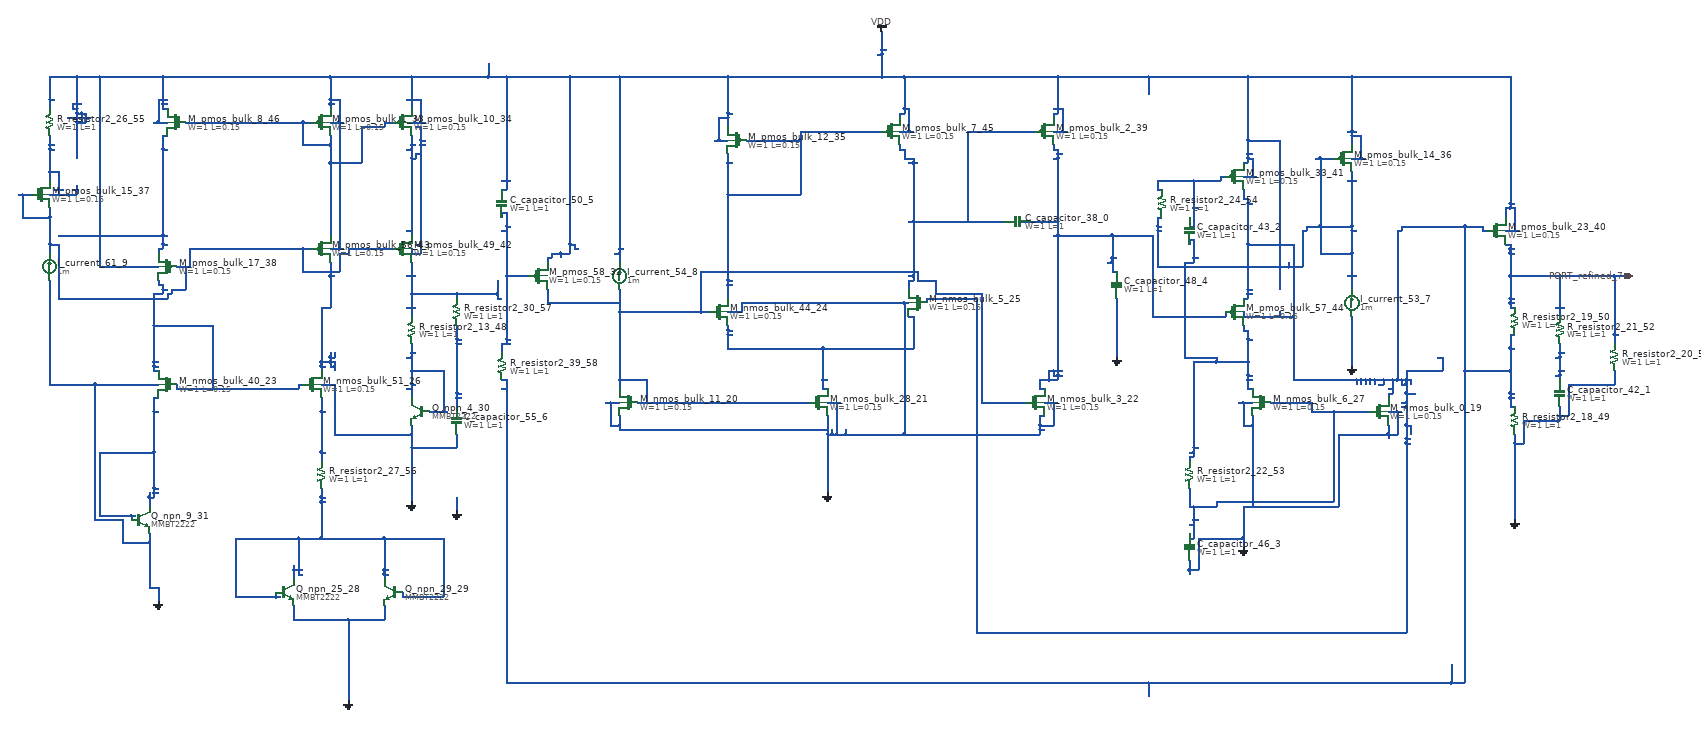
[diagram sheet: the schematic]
v {xschem version=3.4.8 file_version=1.2}
G {}
K {}
V {}
S {}
E {}
C {sky130_fd_pr/cap_mim_m3_1.sym} 2260 500 1 0 {name="C_capacitor_38_0" model=cap_mim_m3_1 W=1 L=1 MF=1 spiceprefix=X}
C {sky130_fd_pr/cap_mim_m3_1.sym} 3460 880 2 0 {name="C_capacitor_42_1" model=cap_mim_m3_1 W=1 L=1 MF=1 spiceprefix=X}
C {sky130_fd_pr/cap_mim_m3_1.sym} 2640 520 2 0 {name="C_capacitor_43_2" model=cap_mim_m3_1 W=1 L=1 MF=1 spiceprefix=X}
C {sky130_fd_pr/cap_mim_m3_1.sym} 2640 1220 2 0 {name="C_capacitor_46_3" model=cap_mim_m3_1 W=1 L=1 MF=1 spiceprefix=X}
C {sky130_fd_pr/cap_mim_m3_1.sym} 2480 640 2 0 {name="C_capacitor_48_4" model=cap_mim_m3_1 W=1 L=1 MF=1 spiceprefix=X}
C {sky130_fd_pr/cap_mim_m3_1.sym} 1120 460 2 0 {name="C_capacitor_50_5" model=cap_mim_m3_1 W=1 L=1 MF=1 spiceprefix=X}
C {sky130_fd_pr/cap_mim_m3_1.sym} 1020 940 2 0 {name="C_capacitor_55_6" model=cap_mim_m3_1 W=1 L=1 MF=1 spiceprefix=X}
C {devices/isource.sym} 3000 680 2 0 {name="I_current_53_7" value=1m}
C {devices/isource.sym} 1380 620 2 0 {name="I_current_54_8" value=1m}
C {devices/isource.sym} 120 600 2 0 {name="I_current_61_9" value=1m}
C {devices/gnd.sym} 780 1560 0 0 {name="l_gnd_31_10" lab="GND"}
C {devices/gnd.sym} 360 1340 0 0 {name="l_gnd_32_11" lab="GND"}
C {devices/gnd.sym} 3000 820 0 0 {name="l_gnd_34_12" lab="GND"}
C {devices/gnd.sym} 3360 1160 0 0 {name="l_gnd_35_13" lab="GND"}
C {devices/gnd.sym} 920 1120 0 0 {name="l_gnd_36_14" lab="GND"}
C {devices/gnd.sym} 2480 800 0 0 {name="l_gnd_37_15" lab="GND"}
C {devices/gnd.sym} 1020 1140 0 0 {name="l_gnd_41_16" lab="GND"}
C {devices/gnd.sym} 1840 1100 0 0 {name="l_gnd_45_17" lab="GND"}
C {devices/gnd.sym} 2760 1220 0 0 {name="l_gnd_52_18" lab="GND"}
C {sky130_fd_pr/nfet_01v8.sym} 3060 920 0 0 {name="M_nmos_bulk_0_19"
W=1
L=0.15
nf=1 
mult=1
ad="expr('int((@nf + 1)/2) * @W / @nf * 0.29')"
pd="expr('2*int((@nf + 1)/2) * (@W / @nf + 0.29)')"
as="expr('int((@nf + 2)/2) * @W / @nf * 0.29')"
ps="expr('2*int((@nf + 2)/2) * (@W / @nf + 0.29)')"
nrd="expr('0.29 / @W ')" nrs="expr('0.29 / @W ')"
sa=0 sb=0 sd=0
model=nfet_01v8
spiceprefix=X
}
C {sky130_fd_pr/nfet_01v8.sym} 1400 900 0 1 {name="M_nmos_bulk_11_20"
W=1
L=0.15
nf=1 
mult=1
ad="expr('int((@nf + 1)/2) * @W / @nf * 0.29')"
pd="expr('2*int((@nf + 1)/2) * (@W / @nf + 0.29)')"
as="expr('int((@nf + 2)/2) * @W / @nf * 0.29')"
ps="expr('2*int((@nf + 2)/2) * (@W / @nf + 0.29)')"
nrd="expr('0.29 / @W ')" nrs="expr('0.29 / @W ')"
sa=0 sb=0 sd=0
model=nfet_01v8
spiceprefix=X
}
C {sky130_fd_pr/nfet_01v8.sym} 1820 900 0 0 {name="M_nmos_bulk_28_21"
W=1
L=0.15
nf=1 
mult=1
ad="expr('int((@nf + 1)/2) * @W / @nf * 0.29')"
pd="expr('2*int((@nf + 1)/2) * (@W / @nf + 0.29)')"
as="expr('int((@nf + 2)/2) * @W / @nf * 0.29')"
ps="expr('2*int((@nf + 2)/2) * (@W / @nf + 0.29)')"
nrd="expr('0.29 / @W ')" nrs="expr('0.29 / @W ')"
sa=0 sb=0 sd=0
model=nfet_01v8
spiceprefix=X
}
C {sky130_fd_pr/nfet_01v8.sym} 2300 900 0 0 {name="M_nmos_bulk_3_22"
W=1
L=0.15
nf=1 
mult=1
ad="expr('int((@nf + 1)/2) * @W / @nf * 0.29')"
pd="expr('2*int((@nf + 1)/2) * (@W / @nf + 0.29)')"
as="expr('int((@nf + 2)/2) * @W / @nf * 0.29')"
ps="expr('2*int((@nf + 2)/2) * (@W / @nf + 0.29)')"
nrd="expr('0.29 / @W ')" nrs="expr('0.29 / @W ')"
sa=0 sb=0 sd=0
model=nfet_01v8
spiceprefix=X
}
C {sky130_fd_pr/nfet_01v8.sym} 380 860 0 1 {name="M_nmos_bulk_40_23"
W=1
L=0.15
nf=1 
mult=1
ad="expr('int((@nf + 1)/2) * @W / @nf * 0.29')"
pd="expr('2*int((@nf + 1)/2) * (@W / @nf + 0.29)')"
as="expr('int((@nf + 2)/2) * @W / @nf * 0.29')"
ps="expr('2*int((@nf + 2)/2) * (@W / @nf + 0.29)')"
nrd="expr('0.29 / @W ')" nrs="expr('0.29 / @W ')"
sa=0 sb=0 sd=0
model=nfet_01v8
spiceprefix=X
}
C {sky130_fd_pr/nfet_01v8.sym} 1600 700 0 0 {name="M_nmos_bulk_44_24"
W=1
L=0.15
nf=1 
mult=1
ad="expr('int((@nf + 1)/2) * @W / @nf * 0.29')"
pd="expr('2*int((@nf + 1)/2) * (@W / @nf + 0.29)')"
as="expr('int((@nf + 2)/2) * @W / @nf * 0.29')"
ps="expr('2*int((@nf + 2)/2) * (@W / @nf + 0.29)')"
nrd="expr('0.29 / @W ')" nrs="expr('0.29 / @W ')"
sa=0 sb=0 sd=0
model=nfet_01v8
spiceprefix=X
}
C {sky130_fd_pr/nfet_01v8.sym} 2040 680 0 1 {name="M_nmos_bulk_5_25"
W=1
L=0.15
nf=1 
mult=1
ad="expr('int((@nf + 1)/2) * @W / @nf * 0.29')"
pd="expr('2*int((@nf + 1)/2) * (@W / @nf + 0.29)')"
as="expr('int((@nf + 2)/2) * @W / @nf * 0.29')"
ps="expr('2*int((@nf + 2)/2) * (@W / @nf + 0.29)')"
nrd="expr('0.29 / @W ')" nrs="expr('0.29 / @W ')"
sa=0 sb=0 sd=0
model=nfet_01v8
spiceprefix=X
}
C {sky130_fd_pr/nfet_01v8.sym} 700 860 0 0 {name="M_nmos_bulk_51_26"
W=1
L=0.15
nf=1 
mult=1
ad="expr('int((@nf + 1)/2) * @W / @nf * 0.29')"
pd="expr('2*int((@nf + 1)/2) * (@W / @nf + 0.29)')"
as="expr('int((@nf + 2)/2) * @W / @nf * 0.29')"
ps="expr('2*int((@nf + 2)/2) * (@W / @nf + 0.29)')"
nrd="expr('0.29 / @W ')" nrs="expr('0.29 / @W ')"
sa=0 sb=0 sd=0
model=nfet_01v8
spiceprefix=X
}
C {sky130_fd_pr/nfet_01v8.sym} 2800 900 0 1 {name="M_nmos_bulk_6_27"
W=1
L=0.15
nf=1 
mult=1
ad="expr('int((@nf + 1)/2) * @W / @nf * 0.29')"
pd="expr('2*int((@nf + 1)/2) * (@W / @nf + 0.29)')"
as="expr('int((@nf + 2)/2) * @W / @nf * 0.29')"
ps="expr('2*int((@nf + 2)/2) * (@W / @nf + 0.29)')"
nrd="expr('0.29 / @W ')" nrs="expr('0.29 / @W ')"
sa=0 sb=0 sd=0
model=nfet_01v8
spiceprefix=X
}
C {devices/npn.sym} 640 1320 0 0 {name="Q_npn_25_28"
model=MMBT2222
device=MMBT2222
footprint=SOT23
area=1
m=1}
C {devices/npn.sym} 880 1320 0 1 {name="Q_npn_29_29"
model=MMBT2222
device=MMBT2222
footprint=SOT23
area=1
m=1}
C {devices/npn.sym} 940 920 0 1 {name="Q_npn_4_30"
model=MMBT2222
device=MMBT2222
footprint=SOT23
area=1
m=1}
C {devices/npn.sym} 320 1160 0 0 {name="Q_npn_9_31"
model=MMBT2222
device=MMBT2222
footprint=SOT23
area=1
m=1}
C {sky130_fd_pr/pfet3_01v8.sym} 1200 620 0 0 {name="M_pmos_58_32"
W=1
L=0.15
body=VDD
nf=1
mult=1
ad="expr('int((@nf + 1)/2) * @W / @nf * 0.29')"
pd="expr('2*int((@nf + 1)/2) * (@W / @nf + 0.29)')"
as="expr('int((@nf + 2)/2) * @W / @nf * 0.29')"
ps="expr('2*int((@nf + 2)/2) * (@W / @nf + 0.29)')"
nrd="expr('0.29 / @W ')" nrs="expr('0.29 / @W ')"
sa=0 sb=0 sd=0
model=pfet_01v8
spiceprefix=X
}
C {sky130_fd_pr/pfet_01v8.sym} 720 280 0 0 {name="M_pmos_bulk_1_33"
W=1
L=0.15
nf=1
mult=1
ad="expr('int((@nf + 1)/2) * @W / @nf * 0.29')"
pd="expr('2*int((@nf + 1)/2) * (@W / @nf + 0.29)')"
as="expr('int((@nf + 2)/2) * @W / @nf * 0.29')"
ps="expr('2*int((@nf + 2)/2) * (@W / @nf + 0.29)')"
nrd="expr('0.29 / @W ')" nrs="expr('0.29 / @W ')"
sa=0 sb=0 sd=0
model=pfet_01v8
spiceprefix=X
}
C {sky130_fd_pr/pfet_01v8.sym} 900 280 0 0 {name="M_pmos_bulk_10_34"
W=1
L=0.15
nf=1
mult=1
ad="expr('int((@nf + 1)/2) * @W / @nf * 0.29')"
pd="expr('2*int((@nf + 1)/2) * (@W / @nf + 0.29)')"
as="expr('int((@nf + 2)/2) * @W / @nf * 0.29')"
ps="expr('2*int((@nf + 2)/2) * (@W / @nf + 0.29)')"
nrd="expr('0.29 / @W ')" nrs="expr('0.29 / @W ')"
sa=0 sb=0 sd=0
model=pfet_01v8
spiceprefix=X
}
C {sky130_fd_pr/pfet_01v8.sym} 1640 320 0 1 {name="M_pmos_bulk_12_35"
W=1
L=0.15
nf=1
mult=1
ad="expr('int((@nf + 1)/2) * @W / @nf * 0.29')"
pd="expr('2*int((@nf + 1)/2) * (@W / @nf + 0.29)')"
as="expr('int((@nf + 2)/2) * @W / @nf * 0.29')"
ps="expr('2*int((@nf + 2)/2) * (@W / @nf + 0.29)')"
nrd="expr('0.29 / @W ')" nrs="expr('0.29 / @W ')"
sa=0 sb=0 sd=0
model=pfet_01v8
spiceprefix=X
}
C {sky130_fd_pr/pfet_01v8.sym} 2980 360 0 0 {name="M_pmos_bulk_14_36"
W=1
L=0.15
nf=1
mult=1
ad="expr('int((@nf + 1)/2) * @W / @nf * 0.29')"
pd="expr('2*int((@nf + 1)/2) * (@W / @nf + 0.29)')"
as="expr('int((@nf + 2)/2) * @W / @nf * 0.29')"
ps="expr('2*int((@nf + 2)/2) * (@W / @nf + 0.29)')"
nrd="expr('0.29 / @W ')" nrs="expr('0.29 / @W ')"
sa=0 sb=0 sd=0
model=pfet_01v8
spiceprefix=X
}
C {sky130_fd_pr/pfet_01v8.sym} 100 440 0 0 {name="M_pmos_bulk_15_37"
W=1
L=0.15
nf=1
mult=1
ad="expr('int((@nf + 1)/2) * @W / @nf * 0.29')"
pd="expr('2*int((@nf + 1)/2) * (@W / @nf + 0.29)')"
as="expr('int((@nf + 2)/2) * @W / @nf * 0.29')"
ps="expr('2*int((@nf + 2)/2) * (@W / @nf + 0.29)')"
nrd="expr('0.29 / @W ')" nrs="expr('0.29 / @W ')"
sa=0 sb=0 sd=0
model=pfet_01v8
spiceprefix=X
}
C {sky130_fd_pr/pfet_01v8.sym} 380 600 0 1 {name="M_pmos_bulk_17_38"
W=1
L=0.15
nf=1
mult=1
ad="expr('int((@nf + 1)/2) * @W / @nf * 0.29')"
pd="expr('2*int((@nf + 1)/2) * (@W / @nf + 0.29)')"
as="expr('int((@nf + 2)/2) * @W / @nf * 0.29')"
ps="expr('2*int((@nf + 2)/2) * (@W / @nf + 0.29)')"
nrd="expr('0.29 / @W ')" nrs="expr('0.29 / @W ')"
sa=0 sb=0 sd=0
model=pfet_01v8
spiceprefix=X
}
C {sky130_fd_pr/pfet_01v8.sym} 2320 300 0 0 {name="M_pmos_bulk_2_39"
W=1
L=0.15
nf=1
mult=1
ad="expr('int((@nf + 1)/2) * @W / @nf * 0.29')"
pd="expr('2*int((@nf + 1)/2) * (@W / @nf + 0.29)')"
as="expr('int((@nf + 2)/2) * @W / @nf * 0.29')"
ps="expr('2*int((@nf + 2)/2) * (@W / @nf + 0.29)')"
nrd="expr('0.29 / @W ')" nrs="expr('0.29 / @W ')"
sa=0 sb=0 sd=0
model=pfet_01v8
spiceprefix=X
}
C {sky130_fd_pr/pfet_01v8.sym} 3320 520 0 0 {name="M_pmos_bulk_23_40"
W=1
L=0.15
nf=1
mult=1
ad="expr('int((@nf + 1)/2) * @W / @nf * 0.29')"
pd="expr('2*int((@nf + 1)/2) * (@W / @nf + 0.29)')"
as="expr('int((@nf + 2)/2) * @W / @nf * 0.29')"
ps="expr('2*int((@nf + 2)/2) * (@W / @nf + 0.29)')"
nrd="expr('0.29 / @W ')" nrs="expr('0.29 / @W ')"
sa=0 sb=0 sd=0
model=pfet_01v8
spiceprefix=X
}
C {sky130_fd_pr/pfet_01v8.sym} 2740 400 0 0 {name="M_pmos_bulk_33_41"
W=1
L=0.15
nf=1
mult=1
ad="expr('int((@nf + 1)/2) * @W / @nf * 0.29')"
pd="expr('2*int((@nf + 1)/2) * (@W / @nf + 0.29)')"
as="expr('int((@nf + 2)/2) * @W / @nf * 0.29')"
ps="expr('2*int((@nf + 2)/2) * (@W / @nf + 0.29)')"
nrd="expr('0.29 / @W ')" nrs="expr('0.29 / @W ')"
sa=0 sb=0 sd=0
model=pfet_01v8
spiceprefix=X
}
C {sky130_fd_pr/pfet_01v8.sym} 900 560 0 0 {name="M_pmos_bulk_49_42"
W=1
L=0.15
nf=1
mult=1
ad="expr('int((@nf + 1)/2) * @W / @nf * 0.29')"
pd="expr('2*int((@nf + 1)/2) * (@W / @nf + 0.29)')"
as="expr('int((@nf + 2)/2) * @W / @nf * 0.29')"
ps="expr('2*int((@nf + 2)/2) * (@W / @nf + 0.29)')"
nrd="expr('0.29 / @W ')" nrs="expr('0.29 / @W ')"
sa=0 sb=0 sd=0
model=pfet_01v8
spiceprefix=X
}
C {sky130_fd_pr/pfet_01v8.sym} 720 560 2 1 {name="M_pmos_bulk_56_43"
W=1
L=0.15
nf=1
mult=1
ad="expr('int((@nf + 1)/2) * @W / @nf * 0.29')"
pd="expr('2*int((@nf + 1)/2) * (@W / @nf + 0.29)')"
as="expr('int((@nf + 2)/2) * @W / @nf * 0.29')"
ps="expr('2*int((@nf + 2)/2) * (@W / @nf + 0.29)')"
nrd="expr('0.29 / @W ')" nrs="expr('0.29 / @W ')"
sa=0 sb=0 sd=0
model=pfet_01v8
spiceprefix=X
}
C {sky130_fd_pr/pfet_01v8.sym} 2740 700 0 0 {name="M_pmos_bulk_57_44"
W=1
L=0.15
nf=1
mult=1
ad="expr('int((@nf + 1)/2) * @W / @nf * 0.29')"
pd="expr('2*int((@nf + 1)/2) * (@W / @nf + 0.29)')"
as="expr('int((@nf + 2)/2) * @W / @nf * 0.29')"
ps="expr('2*int((@nf + 2)/2) * (@W / @nf + 0.29)')"
nrd="expr('0.29 / @W ')" nrs="expr('0.29 / @W ')"
sa=0 sb=0 sd=0
model=pfet_01v8
spiceprefix=X
}
C {sky130_fd_pr/pfet_01v8.sym} 1980 300 0 0 {name="M_pmos_bulk_7_45"
W=1
L=0.15
nf=1
mult=1
ad="expr('int((@nf + 1)/2) * @W / @nf * 0.29')"
pd="expr('2*int((@nf + 1)/2) * (@W / @nf + 0.29)')"
as="expr('int((@nf + 2)/2) * @W / @nf * 0.29')"
ps="expr('2*int((@nf + 2)/2) * (@W / @nf + 0.29)')"
nrd="expr('0.29 / @W ')" nrs="expr('0.29 / @W ')"
sa=0 sb=0 sd=0
model=pfet_01v8
spiceprefix=X
}
C {sky130_fd_pr/pfet_01v8.sym} 400 280 0 1 {name="M_pmos_bulk_8_46"
W=1
L=0.15
nf=1
mult=1
ad="expr('int((@nf + 1)/2) * @W / @nf * 0.29')"
pd="expr('2*int((@nf + 1)/2) * (@W / @nf + 0.29)')"
as="expr('int((@nf + 2)/2) * @W / @nf * 0.29')"
ps="expr('2*int((@nf + 2)/2) * (@W / @nf + 0.29)')"
nrd="expr('0.29 / @W ')" nrs="expr('0.29 / @W ')"
sa=0 sb=0 sd=0
model=pfet_01v8
spiceprefix=X
}
C {devices/ipin.sym} 3620 620 0 0 {name="p_port_16_47" lab="PORT_refined_7"}
C {sky130_fd_pr/res_generic_po.sym} 920 740 2 0 {name="R_resistor2_13_48"
W=1
L=1
model=res_generic_po
spiceprefix=X
mult=1}
C {sky130_fd_pr/res_generic_po.sym} 3360 940 2 0 {name="R_resistor2_18_49"
W=1
L=1
model=res_generic_po
spiceprefix=X
mult=1}
C {sky130_fd_pr/res_generic_po.sym} 3360 720 2 0 {name="R_resistor2_19_50"
W=1
L=1
model=res_generic_po
spiceprefix=X
mult=1}
C {sky130_fd_pr/res_generic_po.sym} 3580 800 2 0 {name="R_resistor2_20_51"
W=1
L=1
model=res_generic_po
spiceprefix=X
mult=1}
C {sky130_fd_pr/res_generic_po.sym} 3460 740 2 0 {name="R_resistor2_21_52"
W=1
L=1
model=res_generic_po
spiceprefix=X
mult=1}
C {sky130_fd_pr/res_generic_po.sym} 2640 1060 2 0 {name="R_resistor2_22_53"
W=1
L=1
model=res_generic_po
spiceprefix=X
mult=1}
C {sky130_fd_pr/res_generic_po.sym} 2580 460 2 0 {name="R_resistor2_24_54"
W=1
L=1
model=res_generic_po
spiceprefix=X
mult=1}
C {sky130_fd_pr/res_generic_po.sym} 120 280 2 0 {name="R_resistor2_26_55"
W=1
L=1
model=res_generic_po
spiceprefix=X
mult=1}
C {sky130_fd_pr/res_generic_po.sym} 720 1060 2 0 {name="R_resistor2_27_56"
W=1
L=1
model=res_generic_po
spiceprefix=X
mult=1}
C {sky130_fd_pr/res_generic_po.sym} 1020 700 2 0 {name="R_resistor2_30_57"
W=1
L=1
model=res_generic_po
spiceprefix=X
mult=1}
C {sky130_fd_pr/res_generic_po.sym} 1120 820 2 0 {name="R_resistor2_39_58"
W=1
L=1
model=res_generic_po
spiceprefix=X
mult=1}
C {devices/vdd.sym} 1960 80 0 0 {name="l_vdd_47_59" lab="VDD"}
N 2020 630 2030 630 {}
N 2020 620 2030 620 {}
N 2020 500 2030 500 {}
N 2030 500 2150 500 {}
N 2150 500 2230 500 {}
N 2020 370 2030 370 {}
N 2030 370 2040 370 {}
N 2010 360 2030 360 {}
N 2000 340 2010 340 {}
N 2150 300 2300 300 {}
N 2000 340 2000 330 {}
N 2010 360 2010 340 {}
N 2020 650 2020 630 {}
N 2030 630 2030 620 {}
N 2030 620 2030 500 {}
N 2030 500 2030 370 {}
N 2030 370 2030 360 {}
N 2150 500 2150 300 {}
N 2310 870 2320 870 {}
N 2310 850 2330 850 {}
N 2330 850 2350 850 {}
N 2340 840 2350 840 {}
N 2350 840 2360 840 {}
N 2330 830 2340 830 {}
N 2340 830 2350 830 {}
N 2350 830 2360 830 {}
N 2560 710 2720 710 {}
N 2470 610 2480 610 {}
N 2460 590 2470 590 {}
N 2470 580 2480 580 {}
N 2340 530 2350 530 {}
N 2350 530 2470 530 {}
N 2470 530 2560 530 {}
N 2270 500 2290 500 {}
N 2290 500 2350 500 {}
N 2340 360 2350 360 {}
N 2350 350 2360 350 {}
N 2340 340 2350 340 {}
N 2310 870 2310 850 {}
N 2330 850 2330 830 {}
N 2340 840 2340 830 {}
N 2340 340 2340 330 {}
N 2350 850 2350 840 {}
N 2350 840 2350 830 {}
N 2350 830 2350 530 {}
N 2350 530 2350 500 {}
N 2350 500 2350 360 {}
N 2350 360 2350 350 {}
N 2350 350 2350 340 {}
N 2470 610 2470 590 {}
N 2470 590 2470 580 {}
N 2470 580 2470 530 {}
N 2560 710 2560 530 {}
N 2720 710 2720 700 {}
N 920 570 940 570 {}
N 930 550 940 550 {}
N 910 520 920 520 {}
N 920 360 930 360 {}
N 930 350 940 350 {}
N 910 340 920 340 {}
N 920 330 930 330 {}
N 940 330 950 330 {}
N 940 320 950 320 {}
N 930 290 940 290 {}
N 920 570 920 560 {}
N 920 530 920 520 {}
N 920 520 920 360 {}
N 920 360 920 340 {}
N 920 340 920 330 {}
N 920 330 920 310 {}
N 930 360 930 350 {}
N 940 570 940 550 {}
N 940 550 940 350 {}
N 940 350 940 330 {}
N 940 330 940 320 {}
N 940 320 940 290 {}
N 910 690 920 690 {}
N 920 690 930 690 {}
N 1110 670 1120 670 {}
N 920 660 1020 660 {}
N 1020 660 1110 660 {}
N 910 620 920 620 {}
N 920 620 930 620 {}
N 920 710 920 690 {}
N 920 690 920 660 {}
N 920 660 920 620 {}
N 920 620 920 590 {}
N 1020 670 1020 660 {}
N 1110 670 1110 660 {}
N 1110 660 1110 630 {}
N 1020 890 1030 890 {}
N 1020 880 1030 880 {}
N 1020 770 1030 770 {}
N 1020 760 1030 760 {}
N 1020 910 1020 890 {}
N 1020 890 1020 880 {}
N 1020 880 1020 770 {}
N 1020 770 1020 760 {}
N 1020 760 1020 730 {}
N 720 820 730 820 {}
N 740 820 750 820 {}
N 720 810 740 810 {}
N 740 810 750 810 {}
N 740 800 750 800 {}
N 720 690 740 690 {}
N 740 620 750 620 {}
N 720 830 720 820 {}
N 720 820 720 810 {}
N 720 810 720 690 {}
N 740 820 740 810 {}
N 740 810 740 800 {}
N 740 800 740 790 {}
N 740 690 740 620 {}
N 740 620 740 590 {}
N 750 830 750 820 {}
N 750 820 750 810 {}
N 750 800 750 790 {}
N 2640 1020 2650 1020 {}
N 2640 1010 2650 1010 {}
N 2650 1000 2660 1000 {}
N 2770 870 2780 870 {}
N 2770 850 2780 850 {}
N 2770 840 2780 840 {}
N 2650 810 2700 810 {}
N 2700 810 2770 810 {}
N 2630 800 2700 800 {}
N 2770 760 2780 760 {}
N 2760 740 2770 740 {}
N 2630 590 2650 590 {}
N 2650 580 2660 580 {}
N 2640 540 2650 540 {}
N 2630 800 2630 590 {}
N 2640 1030 2640 1020 {}
N 2640 550 2640 540 {}
N 2650 1020 2650 1010 {}
N 2650 1010 2650 1000 {}
N 2650 1000 2650 810 {}
N 2650 590 2650 580 {}
N 2650 580 2650 540 {}
N 2700 810 2700 800 {}
N 2760 740 2760 730 {}
N 2770 870 2770 850 {}
N 2770 850 2770 840 {}
N 2770 840 2770 810 {}
N 2770 810 2770 760 {}
N 2770 760 2770 740 {}
N 660 1380 780 1380 {}
N 780 1380 860 1380 {}
N 340 1310 360 1310 {}
N 2640 1270 2660 1270 {}
N 280 1210 340 1210 {}
N 2660 1200 2760 1200 {}
N 220 1160 280 1160 {}
N 2760 1130 2780 1130 {}
N 2780 1130 2970 1130 {}
N 920 1000 1020 1000 {}
N 3360 990 3380 990 {}
N 750 970 920 970 {}
N 1840 970 1850 970 {}
N 1850 970 1860 970 {}
N 1860 970 1880 970 {}
N 1880 970 2010 970 {}
N 2010 970 2310 970 {}
N 2970 970 3080 970 {}
N 3080 970 3100 970 {}
N 1380 960 1840 960 {}
N 2310 960 2320 960 {}
N 1360 950 1380 950 {}
N 2310 950 2340 950 {}
N 2760 950 2780 950 {}
N 3380 940 3460 940 {}
N 2310 930 2320 930 {}
N 3460 930 3480 930 {}
N 3080 920 3100 920 {}
N 3100 920 3110 920 {}
N 1350 900 1360 900 {}
N 1360 900 1380 900 {}
N 1840 900 1860 900 {}
N 1860 900 1870 900 {}
N 2320 900 2340 900 {}
N 2340 900 2350 900 {}
N 2750 900 2760 900 {}
N 2760 900 2780 900 {}
N 120 860 220 860 {}
N 220 860 360 860 {}
N 720 860 750 860 {}
N 3480 860 3580 860 {}
N 1620 700 1650 700 {}
N 1650 680 2010 680 {}
N 2010 680 2020 680 {}
N 120 860 120 630 {}
N 220 1160 220 860 {}
N 280 1210 280 1160 {}
N 340 1310 340 1210 {}
N 340 1210 340 1190 {}
N 360 1340 360 1310 {}
N 660 1380 660 1350 {}
N 750 970 750 860 {}
N 780 1560 780 1380 {}
N 860 1380 860 1350 {}
N 920 1120 920 1000 {}
N 920 1000 920 970 {}
N 920 970 920 950 {}
N 1020 1140 1020 1110 {}
N 1020 1000 1020 970 {}
N 1360 950 1360 900 {}
N 1380 960 1380 950 {}
N 1380 950 1380 930 {}
N 1650 700 1650 680 {}
N 1840 1100 1840 970 {}
N 1840 970 1840 960 {}
N 1840 960 1840 930 {}
N 1850 970 1850 960 {}
N 1860 970 1860 900 {}
N 1880 970 1880 960 {}
N 2010 970 2010 680 {}
N 2310 970 2310 960 {}
N 2310 960 2310 950 {}
N 2310 950 2310 930 {}
N 2340 950 2340 900 {}
N 2480 800 2480 670 {}
N 2640 1280 2640 1270 {}
N 2640 1270 2640 1250 {}
N 2660 1270 2660 1200 {}
N 2760 1220 2760 1200 {}
N 2760 1200 2760 1130 {}
N 2760 950 2760 900 {}
N 2780 1130 2780 950 {}
N 2780 950 2780 930 {}
N 2970 1130 2970 970 {}
N 3000 820 3000 710 {}
N 3080 980 3080 970 {}
N 3080 970 3080 950 {}
N 3100 970 3100 920 {}
N 3360 1160 3360 990 {}
N 3360 990 3360 970 {}
N 3380 990 3380 940 {}
N 3460 940 3460 930 {}
N 3460 930 3460 910 {}
N 3480 930 3480 860 {}
N 3580 860 3580 830 {}
N 1620 640 1630 640 {}
N 1620 630 1630 630 {}
N 1620 440 1780 440 {}
N 1620 370 1630 370 {}
N 1660 320 1780 320 {}
N 1780 300 1960 300 {}
N 1620 670 1620 640 {}
N 1620 640 1620 630 {}
N 1620 630 1620 440 {}
N 1620 440 1620 370 {}
N 1620 370 1620 350 {}
N 1780 440 1780 320 {}
N 1780 320 1780 300 {}
N 960 920 990 920 {}
N 990 920 1000 920 {}
N 910 870 920 870 {}
N 920 860 930 860 {}
N 920 830 990 830 {}
N 910 800 920 800 {}
N 920 790 930 790 {}
N 920 890 920 870 {}
N 920 870 920 860 {}
N 920 860 920 830 {}
N 920 830 920 800 {}
N 920 800 920 790 {}
N 920 790 920 770 {}
N 990 920 990 830 {}
N 3450 840 3460 840 {}
N 3460 830 3470 830 {}
N 3450 800 3460 800 {}
N 3460 790 3470 790 {}
N 3460 860 3460 850 {}
N 3460 850 3460 840 {}
N 3460 840 3460 830 {}
N 3460 830 3460 800 {}
N 3460 800 3460 790 {}
N 3460 790 3460 770 {}
N 2640 1200 2650 1200 {}
N 2640 1170 2650 1170 {}
N 2650 1160 2660 1160 {}
N 2640 1130 2650 1130 {}
N 2650 1130 2700 1130 {}
N 2700 1120 2960 1120 {}
N 2910 920 2960 920 {}
N 2960 920 3040 920 {}
N 2820 900 2910 900 {}
N 2640 1200 2640 1190 {}
N 2640 1130 2640 1090 {}
N 2650 1200 2650 1170 {}
N 2650 1170 2650 1160 {}
N 2650 1160 2650 1130 {}
N 2700 1130 2700 1120 {}
N 2910 920 2910 900 {}
N 2960 1120 2960 920 {}
N 230 600 360 600 {}
N 1220 580 1230 580 {}
N 1230 570 1250 570 {}
N 1250 570 1270 570 {}
N 1370 570 1380 570 {}
N 740 560 760 560 {}
N 760 560 770 560 {}
N 1280 560 1290 560 {}
N 1380 560 1390 560 {}
N 1270 550 1280 550 {}
N 3340 520 3360 520 {}
N 3360 520 3370 520 {}
N 3340 470 3350 470 {}
N 3350 470 3360 470 {}
N 3350 460 3360 460 {}
N 1120 430 1130 430 {}
N 1120 410 1130 410 {}
N 1130 410 1140 410 {}
N 2760 400 2780 400 {}
N 2780 400 2790 400 {}
N 2760 370 2770 370 {}
N 2770 360 2780 360 {}
N 3000 360 3020 360 {}
N 3020 360 3030 360 {}
N 2770 350 2780 350 {}
N 1590 320 1600 320 {}
N 1600 320 1620 320 {}
N 2770 320 2840 320 {}
N 3000 310 3020 310 {}
N 2000 300 2020 300 {}
N 2020 300 2030 300 {}
N 2340 300 2360 300 {}
N 2360 300 2370 300 {}
N 2990 300 3000 300 {}
N 3000 300 3010 300 {}
N 180 280 190 280 {}
N 190 280 200 280 {}
N 350 280 360 280 {}
N 360 280 380 280 {}
N 740 280 760 280 {}
N 760 280 770 280 {}
N 920 280 940 280 {}
N 940 280 950 280 {}
N 160 270 180 270 {}
N 180 270 190 270 {}
N 190 270 200 270 {}
N 200 270 210 270 {}
N 1600 270 1620 270 {}
N 180 260 190 260 {}
N 190 260 200 260 {}
N 1620 260 1630 260 {}
N 2000 260 2010 260 {}
N 2340 260 2350 260 {}
N 170 250 180 250 {}
N 370 250 380 250 {}
N 2010 250 2020 250 {}
N 2340 250 2350 250 {}
N 2350 250 2360 250 {}
N 170 240 180 240 {}
N 180 240 190 240 {}
N 370 240 380 240 {}
N 740 240 750 240 {}
N 120 230 130 230 {}
N 360 230 370 230 {}
N 370 230 380 230 {}
N 740 230 760 230 {}
N 910 230 920 230 {}
N 920 230 940 230 {}
N 120 180 180 180 {}
N 180 180 230 180 {}
N 230 180 370 180 {}
N 370 180 740 180 {}
N 740 180 920 180 {}
N 920 180 1090 180 {}
N 1090 180 1130 180 {}
N 1130 180 1270 180 {}
N 1270 180 1380 180 {}
N 1380 180 1620 180 {}
N 1620 180 1960 180 {}
N 1960 180 2010 180 {}
N 2010 180 2350 180 {}
N 2350 180 2550 180 {}
N 2550 180 2770 180 {}
N 2770 180 3000 180 {}
N 3000 180 3350 180 {}
N 1950 130 1960 130 {}
N 1960 120 1970 120 {}
N 120 250 120 230 {}
N 120 230 120 180 {}
N 170 250 170 240 {}
N 180 360 180 280 {}
N 180 280 180 270 {}
N 180 270 180 260 {}
N 180 260 180 250 {}
N 180 250 180 240 {}
N 180 240 180 180 {}
N 190 280 190 270 {}
N 190 270 190 260 {}
N 200 280 200 270 {}
N 200 270 200 260 {}
N 230 600 230 180 {}
N 360 280 360 230 {}
N 370 250 370 240 {}
N 370 240 370 230 {}
N 370 230 370 180 {}
N 740 250 740 240 {}
N 740 240 740 230 {}
N 740 230 740 180 {}
N 760 560 760 280 {}
N 760 280 760 230 {}
N 920 250 920 230 {}
N 920 230 920 180 {}
N 940 280 940 230 {}
N 1090 180 1090 150 {}
N 1130 430 1130 410 {}
N 1130 410 1130 180 {}
N 1220 590 1220 580 {}
N 1230 580 1230 570 {}
N 1250 580 1250 570 {}
N 1270 570 1270 550 {}
N 1270 550 1270 180 {}
N 1280 560 1280 550 {}
N 1380 590 1380 570 {}
N 1380 570 1380 560 {}
N 1380 560 1380 180 {}
N 1600 320 1600 270 {}
N 1620 290 1620 270 {}
N 1620 270 1620 260 {}
N 1620 260 1620 180 {}
N 1960 180 1960 130 {}
N 1960 130 1960 120 {}
N 1960 120 1960 80 {}
N 2000 270 2000 260 {}
N 2010 260 2010 250 {}
N 2010 250 2010 180 {}
N 2020 300 2020 250 {}
N 2340 270 2340 260 {}
N 2350 260 2350 250 {}
N 2350 250 2350 180 {}
N 2360 300 2360 250 {}
N 2550 220 2550 180 {}
N 2770 370 2770 360 {}
N 2770 360 2770 350 {}
N 2770 350 2770 320 {}
N 2770 320 2770 180 {}
N 2780 400 2780 360 {}
N 2840 650 2840 320 {}
N 3000 330 3000 310 {}
N 3000 310 3000 300 {}
N 3000 300 3000 180 {}
N 3020 360 3020 310 {}
N 3340 490 3340 470 {}
N 3350 470 3350 460 {}
N 3350 460 3350 180 {}
N 3360 520 3360 470 {}
N 2990 620 3000 620 {}
N 3000 620 3010 620 {}
N 2570 600 2860 600 {}
N 2860 600 2890 600 {}
N 2930 570 3000 570 {}
N 2570 520 2580 520 {}
N 2890 520 2900 520 {}
N 3000 520 3010 520 {}
N 2570 510 2580 510 {}
N 2900 510 2930 510 {}
N 2930 510 3000 510 {}
N 2570 490 2580 490 {}
N 2990 410 3000 410 {}
N 3000 410 3010 410 {}
N 2920 360 2930 360 {}
N 2930 360 2960 360 {}
N 2570 600 2570 520 {}
N 2570 520 2570 510 {}
N 2570 510 2570 490 {}
N 2860 600 2860 590 {}
N 2890 600 2890 520 {}
N 2900 520 2900 510 {}
N 2930 570 2930 510 {}
N 2930 510 2930 360 {}
N 3000 650 3000 620 {}
N 3000 620 3000 570 {}
N 3000 570 3000 520 {}
N 3000 520 3000 510 {}
N 3000 510 3000 410 {}
N 3000 410 3000 390 {}
N 120 440 140 440 {}
N 140 440 180 440 {}
N 130 430 140 430 {}
N 140 430 150 430 {}
N 170 430 180 430 {}
N 120 390 140 390 {}
N 120 340 130 340 {}
N 120 330 130 330 {}
N 120 410 120 390 {}
N 120 390 120 340 {}
N 120 340 120 330 {}
N 120 330 120 310 {}
N 140 440 140 430 {}
N 140 430 140 390 {}
N 180 440 180 430 {}
N 180 430 180 420 {}
N 720 1010 730 1010 {}
N 720 920 730 920 {}
N 720 1030 720 1010 {}
N 720 1010 720 920 {}
N 720 920 720 890 {}
N 530 1330 620 1330 {}
N 620 1330 630 1330 {}
N 900 1330 990 1330 {}
N 670 1280 680 1280 {}
N 860 1280 870 1280 {}
N 660 1270 670 1270 {}
N 670 1270 680 1270 {}
N 860 1270 870 1270 {}
N 530 1200 670 1200 {}
N 670 1200 720 1200 {}
N 720 1200 860 1200 {}
N 860 1200 990 1200 {}
N 720 1120 730 1120 {}
N 720 1110 730 1110 {}
N 530 1330 530 1200 {}
N 620 1330 620 1320 {}
N 660 1290 660 1270 {}
N 660 1270 660 1260 {}
N 670 1280 670 1270 {}
N 670 1270 670 1200 {}
N 720 1200 720 1120 {}
N 720 1120 720 1110 {}
N 720 1110 720 1090 {}
N 860 1290 860 1280 {}
N 860 1280 860 1270 {}
N 860 1270 860 1200 {}
N 900 1330 900 1320 {}
N 990 1330 990 1200 {}
N 1830 870 1840 870 {}
N 1830 850 1840 850 {}
N 1620 780 1830 780 {}
N 1830 780 2030 780 {}
N 1620 750 1630 750 {}
N 1620 740 1630 740 {}
N 2020 710 2030 710 {}
N 1620 780 1620 750 {}
N 1620 750 1620 740 {}
N 1620 740 1620 730 {}
N 1830 870 1830 850 {}
N 1830 850 1830 780 {}
N 2030 780 2030 710 {}
N 230 1150 300 1150 {}
N 300 1150 310 1150 {}
N 340 1110 350 1110 {}
N 350 1100 360 1100 {}
N 350 1090 360 1090 {}
N 230 1010 350 1010 {}
N 350 920 360 920 {}
N 350 890 360 890 {}
N 230 1150 230 1010 {}
N 300 1160 300 1150 {}
N 340 1130 340 1110 {}
N 340 1110 340 1100 {}
N 350 1110 350 1100 {}
N 350 1100 350 1090 {}
N 350 1090 350 1010 {}
N 350 1010 350 920 {}
N 350 920 350 890 {}
N 1420 900 1440 900 {}
N 1440 900 1800 900 {}
N 2180 900 2280 900 {}
N 1380 850 1440 850 {}
N 1380 700 1560 700 {}
N 1560 700 1580 700 {}
N 1220 680 1380 680 {}
N 2080 660 2180 660 {}
N 2040 630 2080 630 {}
N 1560 610 2040 610 {}
N 1220 680 1220 650 {}
N 1380 870 1380 850 {}
N 1380 850 1380 700 {}
N 1380 700 1380 680 {}
N 1380 680 1380 650 {}
N 1440 900 1440 850 {}
N 1560 700 1560 610 {}
N 2040 630 2040 610 {}
N 2080 660 2080 630 {}
N 2180 900 2180 660 {}
N 740 370 810 370 {}
N 680 330 740 330 {}
N 810 290 860 290 {}
N 420 280 680 280 {}
N 680 280 700 280 {}
N 860 280 880 280 {}
N 680 330 680 280 {}
N 740 530 740 370 {}
N 740 370 740 330 {}
N 740 330 740 310 {}
N 810 370 810 290 {}
N 860 290 860 280 {}
N 400 870 480 870 {}
N 480 870 670 870 {}
N 670 860 680 860 {}
N 350 830 360 830 {}
N 350 820 360 820 {}
N 350 810 360 810 {}
N 350 730 480 730 {}
N 350 660 370 660 {}
N 370 650 380 650 {}
N 360 640 370 640 {}
N 350 830 350 820 {}
N 350 820 350 810 {}
N 350 810 350 730 {}
N 350 730 350 660 {}
N 360 640 360 630 {}
N 370 660 370 650 {}
N 370 650 370 640 {}
N 400 870 400 860 {}
N 480 870 480 730 {}
N 670 870 670 860 {}
N 360 560 370 560 {}
N 370 550 380 550 {}
N 140 530 370 530 {}
N 370 530 380 530 {}
N 370 340 380 340 {}
N 370 310 380 310 {}
N 360 570 360 560 {}
N 370 560 370 550 {}
N 370 550 370 530 {}
N 370 530 370 340 {}
N 370 340 370 310 {}
N 140 670 380 670 {}
N 380 660 390 660 {}
N 390 650 420 650 {}
N 680 610 760 610 {}
N 400 600 420 600 {}
N 420 600 430 600 {}
N 760 570 780 570 {}
N 430 560 680 560 {}
N 680 560 700 560 {}
N 780 560 880 560 {}
N 120 550 140 550 {}
N 60 490 120 490 {}
N 50 440 60 440 {}
N 60 440 80 440 {}
N 60 490 60 440 {}
N 120 570 120 550 {}
N 120 550 120 490 {}
N 120 490 120 470 {}
N 140 670 140 550 {}
N 380 670 380 660 {}
N 390 660 390 650 {}
N 420 650 420 600 {}
N 430 600 430 560 {}
N 680 610 680 560 {}
N 760 610 760 570 {}
N 780 570 780 560 {}
N 1120 770 1130 770 {}
N 1130 770 1140 770 {}
N 1130 760 1140 760 {}
N 1130 620 1180 620 {}
N 1120 520 1130 520 {}
N 1130 510 1140 510 {}
N 1120 480 1130 480 {}
N 1120 790 1120 770 {}
N 1120 490 1120 480 {}
N 1130 770 1130 760 {}
N 1130 760 1130 620 {}
N 1130 620 1130 520 {}
N 1130 520 1130 510 {}
N 1130 510 1130 480 {}
N 3580 750 3590 750 {}
N 3350 690 3360 690 {}
N 3450 690 3460 690 {}
N 3460 690 3470 690 {}
N 3350 680 3360 680 {}
N 3350 670 3360 670 {}
N 3350 620 3460 620 {}
N 3460 620 3580 620 {}
N 3580 620 3620 620 {}
N 3350 570 3360 570 {}
N 3350 560 3360 560 {}
N 3340 550 3350 550 {}
N 3350 690 3350 680 {}
N 3350 680 3350 670 {}
N 3350 670 3350 620 {}
N 3350 620 3350 570 {}
N 3350 570 3350 560 {}
N 3350 560 3350 550 {}
N 3460 710 3460 690 {}
N 3460 690 3460 620 {}
N 3580 770 3580 750 {}
N 3580 750 3580 620 {}
N 1130 1520 2550 1520 {}
N 2550 1520 3220 1520 {}
N 3220 1520 3250 1520 {}
N 2170 1410 3120 1410 {}
N 3120 990 3130 990 {}
N 3120 980 3130 980 {}
N 3120 950 3130 950 {}
N 3110 910 3120 910 {}
N 3350 910 3360 910 {}
N 3110 900 3120 900 {}
N 3350 890 3360 890 {}
N 3080 880 3090 880 {}
N 3120 880 3140 880 {}
N 3350 880 3360 880 {}
N 1120 870 1130 870 {}
N 3080 870 3090 870 {}
N 3060 860 3070 860 {}
N 3110 860 3120 860 {}
N 1120 850 1130 850 {}
N 2870 850 3010 850 {}
N 3010 850 3020 850 {}
N 3020 850 3030 850 {}
N 3030 850 3040 850 {}
N 3040 850 3050 850 {}
N 3050 850 3070 850 {}
N 3070 850 3090 850 {}
N 3090 850 3100 850 {}
N 3100 850 3110 850 {}
N 3110 850 3120 850 {}
N 3120 850 3130 850 {}
N 3120 830 3200 830 {}
N 3250 830 3350 830 {}
N 3190 800 3200 800 {}
N 3350 780 3360 780 {}
N 3350 750 3360 750 {}
N 2760 710 2840 710 {}
N 2840 710 2870 710 {}
N 2060 670 2170 670 {}
N 2760 670 2770 670 {}
N 2770 660 2780 660 {}
N 2770 650 2780 650 {}
N 2770 550 2870 550 {}
N 3100 520 3110 520 {}
N 3290 520 3300 520 {}
N 3110 510 3250 510 {}
N 3250 510 3290 510 {}
N 2770 460 2780 460 {}
N 2760 450 2770 450 {}
N 1130 1520 1130 870 {}
N 1130 870 1130 850 {}
N 2060 680 2060 670 {}
N 2170 1410 2170 670 {}
N 2550 1550 2550 1520 {}
N 2760 710 2760 700 {}
N 2760 450 2760 430 {}
N 2770 670 2770 660 {}
N 2770 660 2770 650 {}
N 2770 650 2770 550 {}
N 2770 550 2770 460 {}
N 2770 460 2770 450 {}
N 2840 710 2840 700 {}
N 2870 850 2870 710 {}
N 2870 710 2870 550 {}
N 3010 860 3010 850 {}
N 3020 860 3020 850 {}
N 3030 860 3030 850 {}
N 3040 860 3040 850 {}
N 3050 860 3050 850 {}
N 3070 860 3070 850 {}
N 3080 890 3080 880 {}
N 3090 880 3090 870 {}
N 3090 870 3090 850 {}
N 3100 850 3100 520 {}
N 3110 860 3110 850 {}
N 3110 520 3110 510 {}
N 3120 1410 3120 990 {}
N 3120 990 3120 980 {}
N 3120 980 3120 950 {}
N 3120 950 3120 910 {}
N 3120 910 3120 900 {}
N 3120 900 3120 880 {}
N 3120 880 3120 860 {}
N 3120 860 3120 850 {}
N 3120 850 3120 830 {}
N 3130 970 3130 950 {}
N 3130 860 3130 850 {}
N 3200 830 3200 800 {}
N 3220 1520 3220 1480 {}
N 3250 1520 3250 830 {}
N 3250 830 3250 510 {}
N 3290 520 3290 510 {}
N 3350 910 3350 890 {}
N 3350 890 3350 880 {}
N 3350 880 3350 830 {}
N 3350 830 3350 780 {}
N 3350 780 3350 750 {}
N 2640 510 2650 510 {}
N 2650 470 2660 470 {}
N 2570 430 2580 430 {}
N 2570 410 2650 410 {}
N 2650 410 2710 410 {}
N 2710 400 2720 400 {}
N 2570 430 2570 410 {}
N 2640 510 2640 490 {}
N 2650 510 2650 470 {}
N 2650 470 2650 410 {}
N 2710 410 2710 400 {}
